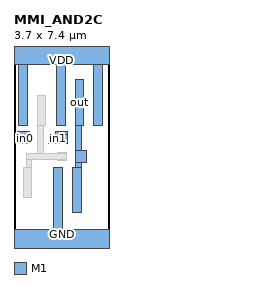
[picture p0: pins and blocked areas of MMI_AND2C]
MACRO MMI_AND2C
	CLASS CORE ;
	FOREIGN MMI_AND2C 0 0 ;
	SIZE 3.7 BY 7.4 ;
	SYMMETRY X Y ;
	SITE CORE1 ;
	PIN out
		DIRECTION output ;
		USE SIGNAL ;
		PORT
			LAYER M1 ;
			RECT 2.38 4.555 2.72 6.315 ;
			LAYER M1 ;
			RECT 2.38 3.555 2.61 4.555 ;
			LAYER M1 ;
			RECT 2.38 3.105 2.815 3.555 ;
			LAYER M1 ;
			RECT 2.38 2.905 2.61 3.105 ;
			LAYER M1 ;
			RECT 2.27 1.145 2.61 2.905 ;
		END
		AntennaDiffArea 1.8768 ;
	END out
	PIN in1
		DIRECTION input ;
		USE SIGNAL ;
		PORT
			LAYER M1 ;
			RECT 1.625 4.19 2.075 4.295 ;
			LAYER M1 ;
			RECT 1.36 3.85 2.075 4.19 ;
			LAYER M1 ;
			RECT 1.625 3.845 2.075 3.85 ;
		END
		AntennaGateArea 0.4464 ;
	END in1
	PIN GND
		DIRECTION inout ;
		USE GROUND ;
		PORT
			LAYER M1 ;
			RECT 1.55 0.5 1.89 2.905 ;
			LAYER M1 ;
			RECT 0 -0.5 3.7 0.5 ;
		END
	END GND
	PIN VDD
		DIRECTION inout ;
		USE POWER ;
		PORT
			LAYER M1 ;
			RECT 0 6.9 3.7 7.9 ;
			LAYER M1 ;
			RECT 0.18 4.555 0.52 6.9 ;
			LAYER M1 ;
			RECT 1.66 4.555 2 6.9 ;
			LAYER M1 ;
			RECT 3.1 4.555 3.44 6.9 ;
		END
	END VDD
	PIN in0
		DIRECTION input ;
		USE SIGNAL ;
		PORT
			LAYER M1 ;
			RECT 0.145 4.19 0.595 4.295 ;
			LAYER M1 ;
			RECT 0.12 3.85 0.595 4.19 ;
			LAYER M1 ;
			RECT 0.145 3.845 0.595 3.85 ;
		END
		AntennaGateArea 0.4464 ;
	END in0
	OBS
		LAYER M1 ;
		RECT 0.9 4.555 1.24 5.715 ;
		LAYER M1 ;
		RECT 0.9 3.445 1.13 4.555 ;
		LAYER M1 ;
		RECT 1.7 3.445 2.04 3.5 ;
		LAYER M1 ;
		RECT 0.47 3.215 2.04 3.445 ;
		LAYER M1 ;
		RECT 0.47 2.905 0.7 3.215 ;
		LAYER M1 ;
		RECT 1.7 3.16 2.04 3.215 ;
		LAYER M1 ;
		RECT 0.36 1.745 0.7 2.905 ;
	END
END MMI_AND2C
